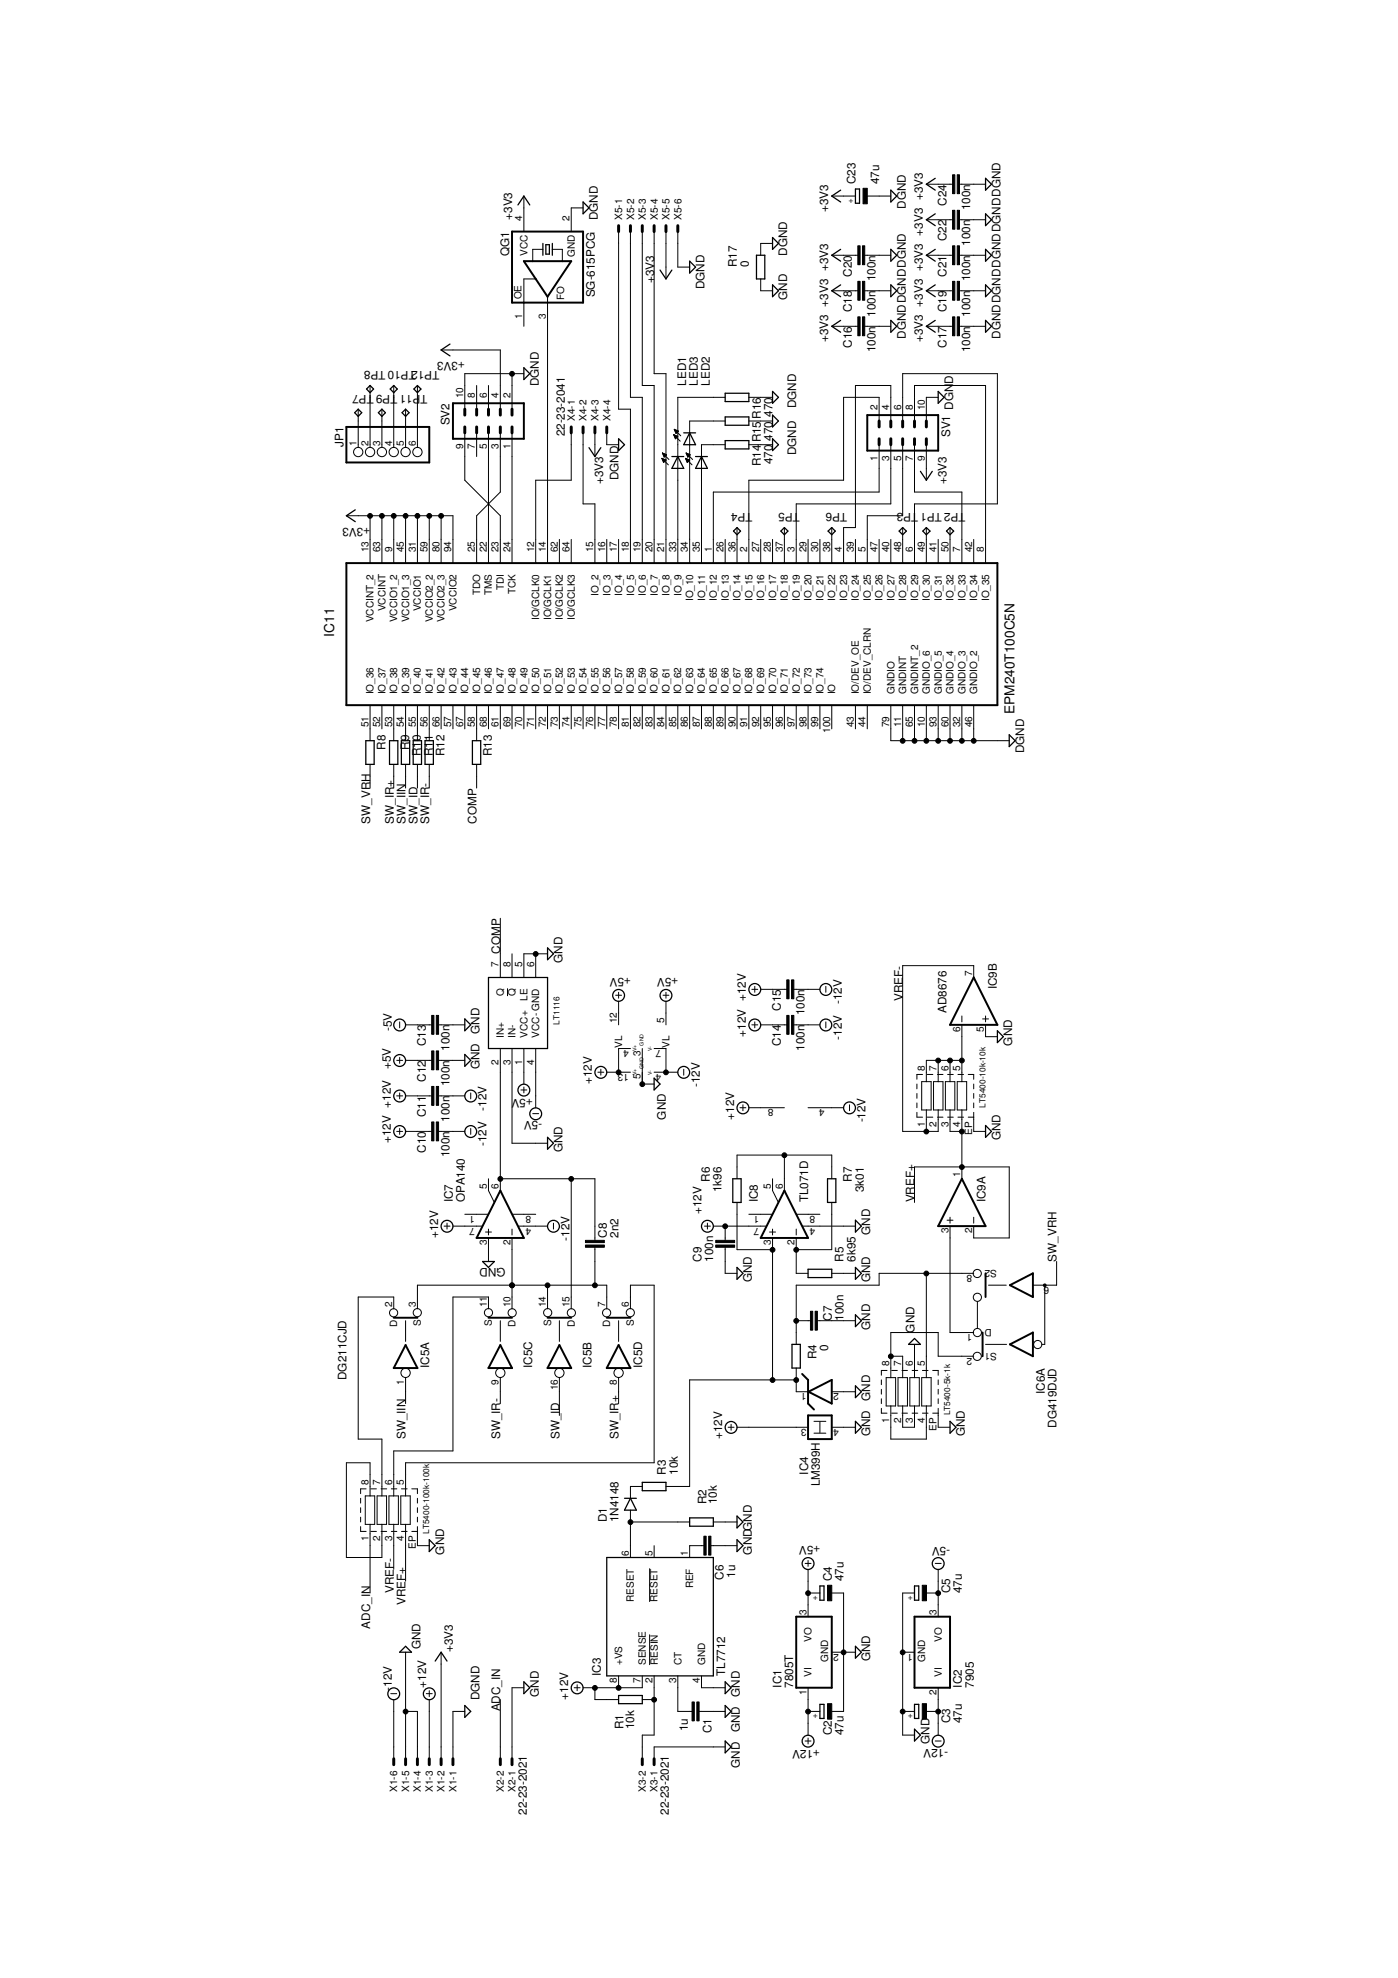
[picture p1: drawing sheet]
<svg xmlns="http://www.w3.org/2000/svg" width="210mm" height="297mm" viewBox="0 0 210 297" stroke-linecap="round" stroke-linejoin="round" font-family="sans-serif">
<defs><g id="words">
<g font-size="2.1">
<text x="50.2" y="95.6" transform="rotate(-90 50.2 95.6)">IC11</text>
<text x="152.3" y="107.2" transform="rotate(-90 152.3 107.2)">EPM240T100C5N</text>
</g>
<g font-size="1.8">
<text x="128.4" y="27.7" transform="rotate(-90 128.4 27.7)">C23</text>
<text x="132" y="27.7" transform="rotate(-90 132 27.7)">47u</text>
<text x="76.9" y="33" transform="rotate(-90 76.9 33)">+3V3</text>
<text x="89.8" y="33.1" transform="rotate(-90 89.8 33.1)">DGND</text>
<text x="124.3" y="31.8" transform="rotate(-90 124.3 31.8)">+3V3</text>
<text x="136" y="31.3" transform="rotate(-90 136 31.3)">DGND</text>
<text x="142.1" y="30.9" transform="rotate(-90 142.1 30.9)">C24</text>
<text x="145.7" y="31.6" transform="rotate(-90 145.7 31.6)">100n</text>
<text x="76.4" y="38.5" transform="rotate(-90 76.4 38.5)">QG1</text>
<text x="110.7" y="40.1" transform="rotate(-90 110.7 40.1)">R17</text>
<text x="112.4" y="40.1" transform="rotate(-90 112.4 40.1)">0</text>
<text x="118.2" y="38.4" transform="rotate(-90 118.2 38.4)">DGND</text>
<text x="127.9" y="41.6" transform="rotate(-90 127.9 41.6)">C20</text>
<text x="142.1" y="41.6" transform="rotate(-90 142.1 41.6)">C21</text>
<text x="142.1" y="36.2" transform="rotate(-90 142.1 36.2)">C22</text>
<text x="145.7" y="36.9" transform="rotate(-90 145.7 36.9)">100n</text>
<text x="89.3" y="44.7" transform="rotate(-90 89.3 44.7)">SG-615PCG</text>
<text x="98.2" y="42.5" transform="rotate(-90 98.2 42.5)">+3V3</text>
<text x="105.8" y="43.4" transform="rotate(-90 105.8 43.4)">DGND</text>
<text x="118.2" y="45" transform="rotate(-90 118.2 45)">GND</text>
<text x="127.9" y="46.9" transform="rotate(-90 127.9 46.9)">C18</text>
<text x="131.5" y="47.6" transform="rotate(-90 131.5 47.6)">100n</text>
<text x="131.5" y="42.3" transform="rotate(-90 131.5 42.3)">100n</text>
<text x="142.1" y="46.9" transform="rotate(-90 142.1 46.9)">C19</text>
<text x="145.7" y="47.6" transform="rotate(-90 145.7 47.6)">100n</text>
<text x="145.7" y="42.3" transform="rotate(-90 145.7 42.3)">100n</text>
<text x="124.3" y="51.4" transform="rotate(-90 124.3 51.4)">+3V3 +3V3 +3V3</text>
<text x="127.9" y="52.2" transform="rotate(-90 127.9 52.2)">C16</text>
<text x="131.5" y="52.9" transform="rotate(-90 131.5 52.9)">100n</text>
<text x="136" y="50.9" transform="rotate(-90 136 50.9)">DGNDDGNDDGND</text>
<text x="138.6" y="51.4" transform="rotate(-90 138.6 51.4)">+3V3 +3V3 +3V3 +3V3 +3V3</text>
<text x="142.1" y="52.2" transform="rotate(-90 142.1 52.2)">C17</text>
<text x="145.7" y="52.9" transform="rotate(-90 145.7 52.9)">100n</text>
<text x="150.2" y="50.9" transform="rotate(-90 150.2 50.9)">DGNDDGNDDGNDDGNDDGND</text>
<text x="64.2" y="59.3" transform="rotate(-180 64.2 59.3)">TP11 TP9 TP7</text>
<text x="66" y="55.8" transform="rotate(-180 66 55.8)">TP12TP10 TP8</text>
<text x="69.8" y="54.3" transform="rotate(-180 69.8 54.3)">+3V3</text>
<text x="80.9" y="58" transform="rotate(-90 80.9 58)">DGND</text>
<text x="103" y="57.9" transform="rotate(-90 103 57.9)">LED1</text>
<text x="104.8" y="57.9" transform="rotate(-90 104.8 57.9)">LED3</text>
<text x="106.6" y="57.9" transform="rotate(-90 106.6 57.9)">LED2</text>
<text x="143.1" y="57.6" transform="rotate(-90 143.1 57.6)">D</text>
<text x="67.5" y="63.9" transform="rotate(-90 67.5 63.9)">SV2</text>
<text x="84.8" y="65.5" transform="rotate(-90 84.8 65.5)">22-23-2041</text>
<text x="116" y="62.6" transform="rotate(-90 116 62.6)">470</text>
<text x="119.5" y="61.3" transform="rotate(-90 119.5 61.3)">DGND</text>
<text x="142.7" y="65.7" transform="rotate(-90 142.7 65.7)">SV1</text>
<text x="143.1" y="61.5" transform="rotate(-90 143.1 61.5)">DGN</text>
<text x="51.6" y="67.1" transform="rotate(-90 51.6 67.1)">JP1</text>
<text x="114.2" y="70" transform="rotate(-90 114.2 70)">R14 R15 R16</text>
<text x="116" y="69.7" transform="rotate(-90 116 69.7)">470</text>
<text x="116" y="66.2" transform="rotate(-90 116 66.2)">470</text>
<text x="119.5" y="68.4" transform="rotate(-90 119.5 68.4)">DGND</text>
<text x="90.6" y="72.7" transform="rotate(-90 90.6 72.7)">+3V3</text>
<text x="92.9" y="72.1" transform="rotate(-90 92.9 72.1)">DGND</text>
<text x="111.9" y="77.1" transform="rotate(-180 111.9 77.1)">P4</text>
<text x="113" y="77.1" transform="rotate(-180 113 77.1)">T</text>
<text x="119" y="77.1" transform="rotate(-180 119 77.1)">P5</text>
<text x="120.1" y="77.1" transform="rotate(-180 120.1 77.1)">T</text>
<text x="127.2" y="77.1" transform="rotate(-180 127.2 77.1)">TP6</text>
<text x="136.8" y="77.1" transform="rotate(-180 136.8 77.1)">P3</text>
<text x="142.1" y="72.7" transform="rotate(-90 142.1 72.7)">+3V3</text>
<text x="143.9" y="77.1" transform="rotate(-180 143.9 77.1)">P2 TP1 T</text>
<text x="145" y="77.1" transform="rotate(-180 145 77.1)">T</text>
<text x="55.6" y="79.2" transform="rotate(-180 55.6 79.2)">+3V3</text>
<text x="57.9" y="112.6" transform="rotate(-90 57.9 112.6)">R8</text>
<text x="61.4" y="112.6" transform="rotate(-90 61.4 112.6)">R9</text>
<text x="63.2" y="113.6" transform="rotate(-90 63.2 113.6)">R10</text>
<text x="65" y="113.6" transform="rotate(-90 65 113.6)">R11</text>
<text x="66.7" y="113.6" transform="rotate(-90 66.7 113.6)">R12</text>
<text x="73.9" y="113.6" transform="rotate(-90 73.9 113.6)">R13</text>
<text x="153.8" y="113.1" transform="rotate(-90 153.8 113.1)">DGND</text>
<text x="55.6" y="123.7" transform="rotate(-90 55.6 123.7)">SW_VRH</text>
<text x="59.1" y="123.7" transform="rotate(-90 59.1 123.7)">SW_IR+</text>
<text x="60.9" y="123.7" transform="rotate(-90 60.9 123.7)">SW_IIN</text>
<text x="62.7" y="123.7" transform="rotate(-90 62.7 123.7)">SW_ID</text>
<text x="64.4" y="123.7" transform="rotate(-90 64.4 123.7)">SW_IR-</text>
<text x="71.6" y="123.7" transform="rotate(-90 71.6 123.7)">COMP</text>
<text x="75.1" y="143.2" transform="rotate(-90 75.1 143.2)">COMP</text>
<text x="84.4" y="144.6" transform="rotate(-90 84.4 144.6)">GND</text>
<text x="94.7" y="146.9" transform="rotate(-180 94.7 146.9)">+5V</text>
<text x="101.8" y="146.9" transform="rotate(-180 101.8 146.9)">+5V</text>
<text x="149.7" y="148.6" transform="rotate(-90 149.7 148.6)">IC9B</text>
<text x="58.9" y="154.9" transform="rotate(-90 58.9 154.9)">-5V</text>
<text x="72" y="155.2" transform="rotate(-90 72 155.2)">GND</text>
<text x="112" y="155.7" transform="rotate(-90 112 155.7)">+12V +12V</text>
<text x="117.2" y="151.8" transform="rotate(-90 117.2 151.8)">C15</text>
<text x="120.8" y="152.5" transform="rotate(-90 120.8 152.5)">100n</text>
<text x="126.4" y="150.8" transform="rotate(-90 126.4 150.8)">-12V</text>
<text x="135.5" y="150.3" transform="rotate(-90 135.5 150.3)">VREF-</text>
<text x="142.1" y="152.1" transform="rotate(-90 142.1 152.1)">AD8676</text>
<text x="58.7" y="160.6" transform="rotate(-90 58.7 160.6)">+5V</text>
<text x="63.9" y="157.1" transform="rotate(-90 63.9 157.1)">C13</text>
<text x="67.5" y="157.8" transform="rotate(-90 67.5 157.8)">100n</text>
<text x="72" y="160.6" transform="rotate(-90 72 160.6)">GND</text>
<text x="117.2" y="157.1" transform="rotate(-90 117.2 157.1)">C14</text>
<text x="120.8" y="157.8" transform="rotate(-90 120.8 157.8)">100n</text>
<text x="126.4" y="156.1" transform="rotate(-90 126.4 156.1)">-12V</text>
<text x="152" y="157" transform="rotate(-90 152 157)">GND</text>
<text x="63.9" y="167.8" transform="rotate(-90 63.9 167.8)">C11</text>
<text x="63.9" y="162.4" transform="rotate(-90 63.9 162.4)">C12</text>
<text x="67.5" y="163.1" transform="rotate(-90 67.5 163.1)">100n</text>
<text x="73.1" y="166.8" transform="rotate(-90 73.1 166.8)">-12V</text>
<text x="80" y="165" transform="rotate(-180 80 165)">+5V</text>
<text x="88.9" y="162.8" transform="rotate(-90 88.9 162.8)">+12V</text>
<text x="105.1" y="163.2" transform="rotate(-90 105.1 163.2)">-12V</text>
<text x="58.7" y="171.7" transform="rotate(-90 58.7 171.7)">+12V +12V</text>
<text x="63.9" y="173.1" transform="rotate(-90 63.9 173.1)">C10</text>
<text x="67.5" y="173.8" transform="rotate(-90 67.5 173.8)">100n</text>
<text x="67.5" y="168.5" transform="rotate(-90 67.5 168.5)">100n</text>
<text x="73.1" y="172.1" transform="rotate(-90 73.1 172.1)">-12V</text>
<text x="81.4" y="168.4" transform="rotate(-180 81.4 168.4)">-5V</text>
<text x="84.4" y="173" transform="rotate(-90 84.4 173)">GND</text>
<text x="100" y="168.1" transform="rotate(-90 100 168.1)">GND</text>
<text x="110.2" y="168.1" transform="rotate(-90 110.2 168.1)">+12V</text>
<text x="129.9" y="168.6" transform="rotate(-90 129.9 168.6)">-12V</text>
<text x="150.2" y="171.2" transform="rotate(-90 150.2 171.2)">GND</text>
<text x="106.6" y="177.5" transform="rotate(-90 106.6 177.5)">R6</text>
<text x="108.4" y="179" transform="rotate(-90 108.4 179)">1k96</text>
<text x="127.9" y="177.5" transform="rotate(-90 127.9 177.5)">R7</text>
<text x="129.7" y="179" transform="rotate(-90 129.7 179)">3k01</text>
<text x="65.8" y="185.9" transform="rotate(-90 65.8 185.9)">+12V</text>
<text x="68" y="180.6" transform="rotate(-90 68 180.6)">IC7</text>
<text x="69.8" y="180.6" transform="rotate(-90 69.8 180.6)">OPA140</text>
<text x="91.1" y="185.9" transform="rotate(-90 91.1 185.9)">C8</text>
<text x="92.9" y="185.9" transform="rotate(-90 92.9 185.9)">2n2</text>
<text x="105.3" y="182.3" transform="rotate(-90 105.3 182.3)">+12V</text>
<text x="113.8" y="180.6" transform="rotate(-90 113.8 180.6)">IC8</text>
<text x="121.3" y="180.6" transform="rotate(-90 121.3 180.6)">TL071D</text>
<text x="130.7" y="185.5" transform="rotate(-90 130.7 185.5)">GND</text>
<text x="137.3" y="180.6" transform="rotate(-90 137.3 180.6)">VREF+</text>
<text x="148" y="180.6" transform="rotate(-90 148 180.6)">IC9A</text>
<text x="75.9" y="190.4" transform="rotate(-180 75.9 190.4)">GND</text>
<text x="85.5" y="186.3" transform="rotate(-90 85.5 186.3)">-12V</text>
<text x="105.3" y="189.5" transform="rotate(-90 105.3 189.5)">C9</text>
<text x="107.1" y="189.5" transform="rotate(-90 107.1 189.5)">100n</text>
<text x="126.7" y="189.5" transform="rotate(-90 126.7 189.5)">R5</text>
<text x="128.4" y="189.5" transform="rotate(-90 128.4 189.5)">6k95</text>
<text x="158.6" y="189.5" transform="rotate(-90 158.6 189.5)">SW_VRH</text>
<text x="112.9" y="192.6" transform="rotate(-90 112.9 192.6)">GND</text>
<text x="130.7" y="192.6" transform="rotate(-90 130.7 192.6)">GND</text>
<text x="124.3" y="202.9" transform="rotate(-90 124.3 202.9)">0</text>
<text x="124.9" y="198.3" transform="rotate(-90 124.9 198.3)">C7</text>
<text x="126.7" y="198.3" transform="rotate(-90 126.7 198.3)">100n</text>
<text x="130.7" y="199.7" transform="rotate(-90 130.7 199.7)">GND</text>
<text x="137.3" y="200.1" transform="rotate(-90 137.3 200.1)">GND</text>
<text x="52" y="207.2" transform="rotate(-90 52 207.2)">DG211CJD</text>
<text x="64.4" y="205.5" transform="rotate(-90 64.4 205.5)">IC5A</text>
<text x="79.9" y="205.5" transform="rotate(-90 79.9 205.5)">IC5C</text>
<text x="88.8" y="205.5" transform="rotate(-90 88.8 205.5)">IC5B</text>
<text x="96.4" y="205.5" transform="rotate(-90 96.4 205.5)">IC5D</text>
<text x="122.6" y="204.1" transform="rotate(-90 122.6 204.1)">R4</text>
<text x="156.9" y="209.3" transform="rotate(-90 156.9 209.3)">IC6A</text>
<text x="130.7" y="215.7" transform="rotate(-90 130.7 215.7)">GND</text>
<text x="130.7" y="210.3" transform="rotate(-90 130.7 210.3)">GND</text>
<text x="144.9" y="215.7" transform="rotate(-90 144.9 215.7)">GND</text>
<text x="158.6" y="214.4" transform="rotate(-90 158.6 214.4)">DG419DJD</text>
<text x="60.9" y="216.1" transform="rotate(-90 60.9 216.1)">SW_IIN</text>
<text x="75.1" y="216.1" transform="rotate(-90 75.1 216.1)">SW_IR-</text>
<text x="84" y="216.1" transform="rotate(-90 84 216.1)">SW_ID</text>
<text x="92.9" y="216.1" transform="rotate(-90 92.9 216.1)">SW_IR+</text>
<text x="100" y="221.5" transform="rotate(-90 100 221.5)">R3</text>
<text x="101.8" y="221.5" transform="rotate(-90 101.8 221.5)">10k</text>
<text x="108.4" y="216.1" transform="rotate(-90 108.4 216.1)">+12V</text>
<text x="121.3" y="221.5" transform="rotate(-90 121.3 221.5)">IC4</text>
<text x="106.1" y="225.9" transform="rotate(-90 106.1 225.9)">R2</text>
<text x="107.6" y="225.9" transform="rotate(-90 107.6 225.9)">10k</text>
<text x="123.1" y="223.2" transform="rotate(-90 123.1 223.2)">LM399H</text>
<text x="66.7" y="233.5" transform="rotate(-90 66.7 233.5)">GND</text>
<text x="91.1" y="228.6" transform="rotate(-90 91.1 228.6)">D1</text>
<text x="92.9" y="228.6" transform="rotate(-90 92.9 228.6)">1N4148</text>
<text x="112.9" y="233.5" transform="rotate(-90 112.9 233.5)">GNDGND</text>
<text x="123.2" y="232.2" transform="rotate(-180 123.2 232.2)">+5V</text>
<text x="142.6" y="232.4" transform="rotate(-180 142.6 232.4)">-5V</text>
<text x="59.1" y="239.2" transform="rotate(-90 59.1 239.2)">VREF-</text>
<text x="108.6" y="237.2" transform="rotate(-90 108.6 237.2)">C6</text>
<text x="110.4" y="236.9" transform="rotate(-90 110.4 236.9)">1u</text>
<text x="124.9" y="237.5" transform="rotate(-90 124.9 237.5)">C4</text>
<text x="126.7" y="237.5" transform="rotate(-90 126.7 237.5)">47u</text>
<text x="142.6" y="239.2" transform="rotate(-90 142.6 239.2)">C5</text>
<text x="144.4" y="239.2" transform="rotate(-90 144.4 239.2)">47u</text>
<text x="55.6" y="244.6" transform="rotate(-90 55.6 244.6)">ADC_IN</text>
<text x="60.9" y="241" transform="rotate(-90 60.9 241)">VREF+</text>
<text x="63.1" y="247.7" transform="rotate(-90 63.1 247.7)">GND</text>
<text x="68" y="248.1" transform="rotate(-90 68 248.1)">+3V3</text>
<text x="90.2" y="251.7" transform="rotate(-90 90.2 251.7)">IC3</text>
<text x="108.9" y="251.7" transform="rotate(-90 108.9 251.7)">TL7712</text>
<text x="130.7" y="249.5" transform="rotate(-90 130.7 249.5)">GND</text>
<text x="58.8" y="253.9" transform="rotate(-90 58.8 253.9)">-12V</text>
<text x="64" y="253.5" transform="rotate(-90 64 253.5)">+12V</text>
<text x="72" y="255.3" transform="rotate(-90 72 255.3)">DGND</text>
<text x="75.1" y="257" transform="rotate(-90 75.1 257)">ADC_IN</text>
<text x="80.9" y="254.8" transform="rotate(-90 80.9 254.8)">GND</text>
<text x="85.3" y="255.2" transform="rotate(-90 85.3 255.2)">+12V</text>
<text x="111.1" y="254.8" transform="rotate(-90 111.1 254.8)">GND</text>
<text x="117.3" y="253.5" transform="rotate(-90 117.3 253.5)">IC1</text>
<text x="119.1" y="253.5" transform="rotate(-90 119.1 253.5)">7805T</text>
<text x="144.4" y="253.5" transform="rotate(-90 144.4 253.5)">IC2</text>
<text x="146.2" y="253.5" transform="rotate(-90 146.2 253.5)">7905</text>
<text x="93.6" y="259.7" transform="rotate(-90 93.6 259.7)">R1</text>
<text x="95.2" y="259.7" transform="rotate(-90 95.2 259.7)">10k</text>
<text x="103.3" y="260" transform="rotate(-90 103.3 260)">1u</text>
<text x="106.8" y="260.3" transform="rotate(-90 106.8 260.3)">C1</text>
<text x="111.1" y="260.1" transform="rotate(-90 111.1 260.1)">GND</text>
<text x="123.1" y="262.8" transform="rotate(-180 123.1 262.8)">+12V</text>
<text x="124.9" y="260.6" transform="rotate(-90 124.9 260.6)">C2</text>
<text x="126.7" y="260.6" transform="rotate(-90 126.7 260.6)">47u</text>
<text x="139.5" y="261.9" transform="rotate(-90 139.5 261.9)">GND</text>
<text x="142.4" y="262.6" transform="rotate(-180 142.4 262.6)">-12V</text>
<text x="142.6" y="258.8" transform="rotate(-90 142.6 258.8)">C3</text>
<text x="144.4" y="258.8" transform="rotate(-90 144.4 258.8)">47u</text>
<text x="111.1" y="265.5" transform="rotate(-90 111.1 265.5)">GND</text>
<text x="79.1" y="272.6" transform="rotate(-90 79.1 272.6)">22-23-2021</text>
<text x="100.4" y="272.6" transform="rotate(-90 100.4 272.6)">22-23-2021</text>
</g>
<g font-size="1.5">
<text x="78.4" y="33.2" transform="rotate(-90 78.4 33.2)">4</text>
<text x="85.5" y="33.2" transform="rotate(-90 85.5 33.2)">2</text>
<text x="93.4" y="33" transform="rotate(-90 93.4 33)">X5-1</text>
<text x="95.2" y="33" transform="rotate(-90 95.2 33)">X5-2</text>
<text x="97" y="33" transform="rotate(-90 97 33)">X5-3</text>
<text x="98.7" y="33" transform="rotate(-90 98.7 33)">X5-4</text>
<text x="100.5" y="33" transform="rotate(-90 100.5 33)">X5-5</text>
<text x="102.3" y="33" transform="rotate(-90 102.3 33)">X5-6</text>
<text x="79.2" y="38.4" transform="rotate(-90 79.2 38.4)">VCC</text>
<text x="86.3" y="38.6" transform="rotate(-90 86.3 38.6)">GND</text>
<text x="78.3" y="45" transform="rotate(-90 78.3 45)">OE</text>
<text x="78.4" y="47.9" transform="rotate(-90 78.4 47.9)">1</text>
<text x="82" y="47.9" transform="rotate(-90 82 47.9)">3</text>
<text x="84.7" y="45.1" transform="rotate(-90 84.7 45.1)">FO</text>
<text x="69.5" y="59.8" transform="rotate(-90 69.5 59.8)">10</text>
<text x="71.3" y="59.8" transform="rotate(-90 71.3 59.8)">8</text>
<text x="73.1" y="59.8" transform="rotate(-90 73.1 59.8)">6</text>
<text x="74.9" y="59.8" transform="rotate(-90 74.9 59.8)">4</text>
<text x="76.6" y="59.8" transform="rotate(-90 76.6 59.8)">2</text>
<text x="86.3" y="63.2" transform="rotate(-90 86.3 63.2)">X4-1</text>
<text x="88.1" y="63.2" transform="rotate(-90 88.1 63.2)">X4-2</text>
<text x="89.9" y="63.2" transform="rotate(-90 89.9 63.2)">X4-3</text>
<text x="91.6" y="63.2" transform="rotate(-90 91.6 63.2)">X4-4</text>
<text x="131.7" y="61.6" transform="rotate(-90 131.7 61.6)">2</text>
<text x="133.5" y="61.6" transform="rotate(-90 133.5 61.6)">4</text>
<text x="135.3" y="61.6" transform="rotate(-90 135.3 61.6)">6</text>
<text x="137.1" y="61.6" transform="rotate(-90 137.1 61.6)">8</text>
<text x="138.8" y="61.6" transform="rotate(-90 138.8 61.6)">10</text>
<text x="53.5" y="66.9" transform="rotate(-90 53.5 66.9)">1</text>
<text x="55.3" y="66.9" transform="rotate(-90 55.3 66.9)">2</text>
<text x="57.1" y="66.9" transform="rotate(-90 57.1 66.9)">3</text>
<text x="58.9" y="66.9" transform="rotate(-90 58.9 66.9)">4</text>
<text x="60.6" y="66.9" transform="rotate(-90 60.6 66.9)">5</text>
<text x="62.4" y="66.9" transform="rotate(-90 62.4 66.9)">6</text>
<text x="69.5" y="67.5" transform="rotate(-90 69.5 67.5)">9</text>
<text x="71.3" y="67.5" transform="rotate(-90 71.3 67.5)">7</text>
<text x="73.1" y="67.5" transform="rotate(-90 73.1 67.5)">5</text>
<text x="74.9" y="67.5" transform="rotate(-90 74.9 67.5)">3</text>
<text x="76.6" y="67.5" transform="rotate(-90 76.6 67.5)">1</text>
<text x="131.7" y="69.2" transform="rotate(-90 131.7 69.2)">1</text>
<text x="133.5" y="69.2" transform="rotate(-90 133.5 69.2)">3</text>
<text x="135.3" y="69.2" transform="rotate(-90 135.3 69.2)">5</text>
<text x="137.1" y="69.2" transform="rotate(-90 137.1 69.2)">7</text>
<text x="138.8" y="69.2" transform="rotate(-90 138.8 69.2)">9</text>
<text x="55.3" y="82.9" transform="rotate(-90 55.3 82.9)">13</text>
<text x="57.1" y="82.9" transform="rotate(-90 57.1 82.9)">63</text>
<text x="58.9" y="82.9" transform="rotate(-90 58.9 82.9)">9</text>
<text x="60.6" y="82.9" transform="rotate(-90 60.6 82.9)">45</text>
<text x="62.4" y="82.9" transform="rotate(-90 62.4 82.9)">31</text>
<text x="64.2" y="82.9" transform="rotate(-90 64.2 82.9)">59</text>
<text x="66" y="82.9" transform="rotate(-90 66 82.9)">80</text>
<text x="67.8" y="82.9" transform="rotate(-90 67.8 82.9)">94</text>
<text x="71.3" y="82.9" transform="rotate(-90 71.3 82.9)">25</text>
<text x="73.1" y="82.9" transform="rotate(-90 73.1 82.9)">22</text>
<text x="74.9" y="82.9" transform="rotate(-90 74.9 82.9)">23</text>
<text x="76.6" y="82.9" transform="rotate(-90 76.6 82.9)">24</text>
<text x="80.2" y="82.9" transform="rotate(-90 80.2 82.9)">12</text>
<text x="82" y="82.9" transform="rotate(-90 82 82.9)">14</text>
<text x="83.7" y="82.9" transform="rotate(-90 83.7 82.9)">62</text>
<text x="85.5" y="82.9" transform="rotate(-90 85.5 82.9)">64</text>
<text x="89.1" y="82.9" transform="rotate(-90 89.1 82.9)">15</text>
<text x="90.9" y="82.9" transform="rotate(-90 90.9 82.9)">16</text>
<text x="92.6" y="82.9" transform="rotate(-90 92.6 82.9)">17</text>
<text x="94.4" y="82.9" transform="rotate(-90 94.4 82.9)">18</text>
<text x="96.2" y="82.9" transform="rotate(-90 96.2 82.9)">19</text>
<text x="98" y="82.9" transform="rotate(-90 98 82.9)">20</text>
<text x="99.7" y="82.9" transform="rotate(-90 99.7 82.9)">21</text>
<text x="101.5" y="82.9" transform="rotate(-90 101.5 82.9)">33</text>
<text x="103.3" y="82.9" transform="rotate(-90 103.3 82.9)">34</text>
<text x="105.1" y="82.9" transform="rotate(-90 105.1 82.9)">35</text>
<text x="106.9" y="82.9" transform="rotate(-90 106.9 82.9)">1</text>
<text x="108.6" y="82.9" transform="rotate(-90 108.6 82.9)">26</text>
<text x="110.4" y="82.9" transform="rotate(-90 110.4 82.9)">36</text>
<text x="112.2" y="82.9" transform="rotate(-90 112.2 82.9)">2</text>
<text x="114" y="82.9" transform="rotate(-90 114 82.9)">27</text>
<text x="115.7" y="82.9" transform="rotate(-90 115.7 82.9)">28</text>
<text x="117.5" y="82.9" transform="rotate(-90 117.5 82.9)">37</text>
<text x="119.3" y="82.9" transform="rotate(-90 119.3 82.9)">3</text>
<text x="121.1" y="82.9" transform="rotate(-90 121.1 82.9)">29</text>
<text x="122.8" y="82.9" transform="rotate(-90 122.8 82.9)">30</text>
<text x="124.6" y="82.9" transform="rotate(-90 124.6 82.9)">38</text>
<text x="126.4" y="82.9" transform="rotate(-90 126.4 82.9)">4</text>
<text x="128.2" y="82.9" transform="rotate(-90 128.2 82.9)">39</text>
<text x="130" y="82.9" transform="rotate(-90 130 82.9)">5</text>
<text x="131.7" y="82.9" transform="rotate(-90 131.7 82.9)">47</text>
<text x="133.5" y="82.9" transform="rotate(-90 133.5 82.9)">40</text>
<text x="135.3" y="82.9" transform="rotate(-90 135.3 82.9)">48</text>
<text x="137.1" y="82.9" transform="rotate(-90 137.1 82.9)">6</text>
<text x="138.8" y="82.9" transform="rotate(-90 138.8 82.9)">49</text>
<text x="140.6" y="82.9" transform="rotate(-90 140.6 82.9)">41</text>
<text x="142.4" y="82.9" transform="rotate(-90 142.4 82.9)">50</text>
<text x="144.2" y="82.9" transform="rotate(-90 144.2 82.9)">7</text>
<text x="146" y="82.9" transform="rotate(-90 146 82.9)">42</text>
<text x="147.7" y="82.9" transform="rotate(-90 147.7 82.9)">8</text>
<text x="72.1" y="89.4" transform="rotate(-90 72.1 89.4)">TDO</text>
<text x="73.9" y="89.4" transform="rotate(-90 73.9 89.4)">TMS</text>
<text x="75.6" y="88.6" transform="rotate(-90 75.6 88.6)">TDI</text>
<text x="77.4" y="89.2" transform="rotate(-90 77.4 89.2)">TCK</text>
<text x="89.9" y="89.5" transform="rotate(-90 89.9 89.5)">IO_2</text>
<text x="91.6" y="89.5" transform="rotate(-90 91.6 89.5)">IO_3</text>
<text x="93.4" y="89.5" transform="rotate(-90 93.4 89.5)">IO_4</text>
<text x="95.2" y="89.5" transform="rotate(-90 95.2 89.5)">IO_5</text>
<text x="97" y="89.5" transform="rotate(-90 97 89.5)">IO_6</text>
<text x="98.7" y="89.5" transform="rotate(-90 98.7 89.5)">IO_7</text>
<text x="100.5" y="89.5" transform="rotate(-90 100.5 89.5)">IO_8</text>
<text x="102.3" y="89.5" transform="rotate(-90 102.3 89.5)">IO_9</text>
<text x="56.1" y="93.5" transform="rotate(-90 56.1 93.5)">VCCINT_2</text>
<text x="57.9" y="91.8" transform="rotate(-90 57.9 91.8)">VCCINT</text>
<text x="59.6" y="93.5" transform="rotate(-90 59.6 93.5)">VCCIO1_2</text>
<text x="61.4" y="93.5" transform="rotate(-90 61.4 93.5)">VCCIO1_3</text>
<text x="63.2" y="91.8" transform="rotate(-90 63.2 91.8)">VCCIO1</text>
<text x="65" y="93.5" transform="rotate(-90 65 93.5)">VCCIO2_2</text>
<text x="66.8" y="93.5" transform="rotate(-90 66.8 93.5)">VCCIO2_3</text>
<text x="68.5" y="91.8" transform="rotate(-90 68.5 91.8)">VCCIO2</text>
<text x="81" y="93.1" transform="rotate(-90 81 93.1)">IO/GCLK0</text>
<text x="82.8" y="93.1" transform="rotate(-90 82.8 93.1)">IO/GCLK1</text>
<text x="84.5" y="93.1" transform="rotate(-90 84.5 93.1)">IO/GCLK2</text>
<text x="86.3" y="93.1" transform="rotate(-90 86.3 93.1)">IO/GCLK3</text>
<text x="104.1" y="90.3" transform="rotate(-90 104.1 90.3)">IO_10</text>
<text x="105.9" y="90.3" transform="rotate(-90 105.9 90.3)">IO_11</text>
<text x="107.6" y="90.3" transform="rotate(-90 107.6 90.3)">IO_12</text>
<text x="109.4" y="90.3" transform="rotate(-90 109.4 90.3)">IO_13</text>
<text x="111.2" y="90.3" transform="rotate(-90 111.2 90.3)">IO_14</text>
<text x="113" y="90.3" transform="rotate(-90 113 90.3)">IO_15</text>
<text x="114.7" y="90.3" transform="rotate(-90 114.7 90.3)">IO_16</text>
<text x="116.5" y="90.3" transform="rotate(-90 116.5 90.3)">IO_17</text>
<text x="118.3" y="90.3" transform="rotate(-90 118.3 90.3)">IO_18</text>
<text x="120.1" y="90.3" transform="rotate(-90 120.1 90.3)">IO_19</text>
<text x="121.9" y="90.3" transform="rotate(-90 121.9 90.3)">IO_20</text>
<text x="123.6" y="90.3" transform="rotate(-90 123.6 90.3)">IO_21</text>
<text x="125.4" y="90.3" transform="rotate(-90 125.4 90.3)">IO_22</text>
<text x="127.2" y="90.3" transform="rotate(-90 127.2 90.3)">IO_23</text>
<text x="129" y="90.3" transform="rotate(-90 129 90.3)">IO_24</text>
<text x="130.7" y="90.3" transform="rotate(-90 130.7 90.3)">IO_25</text>
<text x="132.5" y="90.3" transform="rotate(-90 132.5 90.3)">IO_26</text>
<text x="134.3" y="90.3" transform="rotate(-90 134.3 90.3)">IO_27</text>
<text x="136.1" y="90.3" transform="rotate(-90 136.1 90.3)">IO_28</text>
<text x="137.8" y="90.3" transform="rotate(-90 137.8 90.3)">IO_29</text>
<text x="139.6" y="90.3" transform="rotate(-90 139.6 90.3)">IO_30</text>
<text x="141.4" y="90.3" transform="rotate(-90 141.4 90.3)">IO_31</text>
<text x="143.2" y="90.3" transform="rotate(-90 143.2 90.3)">IO_32</text>
<text x="145" y="90.3" transform="rotate(-90 145 90.3)">IO_33</text>
<text x="146.7" y="90.3" transform="rotate(-90 146.7 90.3)">IO_34</text>
<text x="148.5" y="90.3" transform="rotate(-90 148.5 90.3)">IO_35</text>
<text x="56.1" y="104.3" transform="rotate(-90 56.1 104.3)">IO_36</text>
<text x="57.9" y="104.3" transform="rotate(-90 57.9 104.3)">IO_37</text>
<text x="59.6" y="104.3" transform="rotate(-90 59.6 104.3)">IO_38</text>
<text x="61.4" y="104.3" transform="rotate(-90 61.4 104.3)">IO_39</text>
<text x="63.2" y="104.3" transform="rotate(-90 63.2 104.3)">IO_40</text>
<text x="65" y="104.3" transform="rotate(-90 65 104.3)">IO_41</text>
<text x="66.7" y="104.3" transform="rotate(-90 66.7 104.3)">IO_42</text>
<text x="68.5" y="104.3" transform="rotate(-90 68.5 104.3)">IO_43</text>
<text x="70.3" y="104.3" transform="rotate(-90 70.3 104.3)">IO_44</text>
<text x="72.1" y="104.3" transform="rotate(-90 72.1 104.3)">IO_45</text>
<text x="73.9" y="104.3" transform="rotate(-90 73.9 104.3)">IO_46</text>
<text x="75.6" y="104.3" transform="rotate(-90 75.6 104.3)">IO_47</text>
<text x="77.4" y="104.3" transform="rotate(-90 77.4 104.3)">IO_48</text>
<text x="79.2" y="104.3" transform="rotate(-90 79.2 104.3)">IO_49</text>
<text x="81" y="104.3" transform="rotate(-90 81 104.3)">IO_50</text>
<text x="82.7" y="104.3" transform="rotate(-90 82.7 104.3)">IO_51</text>
<text x="84.5" y="104.3" transform="rotate(-90 84.5 104.3)">IO_52</text>
<text x="86.3" y="104.3" transform="rotate(-90 86.3 104.3)">IO_53</text>
<text x="88.1" y="104.3" transform="rotate(-90 88.1 104.3)">IO_54</text>
<text x="89.9" y="104.3" transform="rotate(-90 89.9 104.3)">IO_55</text>
<text x="91.6" y="104.3" transform="rotate(-90 91.6 104.3)">IO_56</text>
<text x="93.4" y="104.3" transform="rotate(-90 93.4 104.3)">IO_57</text>
<text x="95.2" y="104.3" transform="rotate(-90 95.2 104.3)">IO_58</text>
<text x="97" y="104.3" transform="rotate(-90 97 104.3)">IO_59</text>
<text x="98.7" y="104.3" transform="rotate(-90 98.7 104.3)">IO_60</text>
<text x="100.5" y="104.3" transform="rotate(-90 100.5 104.3)">IO_61</text>
<text x="102.3" y="104.3" transform="rotate(-90 102.3 104.3)">IO_62</text>
<text x="104.1" y="104.3" transform="rotate(-90 104.1 104.3)">IO_63</text>
<text x="105.8" y="104.3" transform="rotate(-90 105.8 104.3)">IO_64</text>
<text x="107.6" y="104.3" transform="rotate(-90 107.6 104.3)">IO_65</text>
<text x="109.4" y="104.3" transform="rotate(-90 109.4 104.3)">IO_66</text>
<text x="111.2" y="104.3" transform="rotate(-90 111.2 104.3)">IO_67</text>
<text x="113" y="104.3" transform="rotate(-90 113 104.3)">IO_68</text>
<text x="114.7" y="104.3" transform="rotate(-90 114.7 104.3)">IO_69</text>
<text x="116.5" y="104.3" transform="rotate(-90 116.5 104.3)">IO_70</text>
<text x="118.3" y="104.3" transform="rotate(-90 118.3 104.3)">IO_71</text>
<text x="120.1" y="104.3" transform="rotate(-90 120.1 104.3)">IO_72</text>
<text x="121.8" y="104.3" transform="rotate(-90 121.8 104.3)">IO_73</text>
<text x="123.6" y="104.3" transform="rotate(-90 123.6 104.3)">IO_74</text>
<text x="125.4" y="104.3" transform="rotate(-90 125.4 104.3)">IO</text>
<text x="129" y="104.3" transform="rotate(-90 129 104.3)">IO/DEV_OE</text>
<text x="130.7" y="104.3" transform="rotate(-90 130.7 104.3)">IO/DEV_CLRN</text>
<text x="134.3" y="104.3" transform="rotate(-90 134.3 104.3)">GNDIO</text>
<text x="136.1" y="104.3" transform="rotate(-90 136.1 104.3)">GNDINT</text>
<text x="137.8" y="104.3" transform="rotate(-90 137.8 104.3)">GNDINT_2</text>
<text x="139.6" y="104.3" transform="rotate(-90 139.6 104.3)">GNDIO_6</text>
<text x="141.4" y="104.3" transform="rotate(-90 141.4 104.3)">GNDIO_5</text>
<text x="143.2" y="104.3" transform="rotate(-90 143.2 104.3)">GNDIO_4</text>
<text x="145" y="104.3" transform="rotate(-90 145 104.3)">GNDIO_3</text>
<text x="146.7" y="104.3" transform="rotate(-90 146.7 104.3)">GNDIO_2</text>
<text x="55.3" y="109.2" transform="rotate(-90 55.3 109.2)">51</text>
<text x="57.1" y="109.2" transform="rotate(-90 57.1 109.2)">52</text>
<text x="58.9" y="109.2" transform="rotate(-90 58.9 109.2)">53</text>
<text x="60.6" y="109.2" transform="rotate(-90 60.6 109.2)">54</text>
<text x="62.4" y="109.2" transform="rotate(-90 62.4 109.2)">55</text>
<text x="64.2" y="109.2" transform="rotate(-90 64.2 109.2)">56</text>
<text x="66" y="109.2" transform="rotate(-90 66 109.2)">66</text>
<text x="67.8" y="109.2" transform="rotate(-90 67.8 109.2)">57</text>
<text x="69.5" y="109.2" transform="rotate(-90 69.5 109.2)">67</text>
<text x="71.3" y="109.2" transform="rotate(-90 71.3 109.2)">58</text>
<text x="73.1" y="109.2" transform="rotate(-90 73.1 109.2)">68</text>
<text x="74.9" y="109.2" transform="rotate(-90 74.9 109.2)">61</text>
<text x="76.6" y="109.2" transform="rotate(-90 76.6 109.2)">69</text>
<text x="78.4" y="109.2" transform="rotate(-90 78.4 109.2)">70</text>
<text x="80.2" y="109.2" transform="rotate(-90 80.2 109.2)">71</text>
<text x="82" y="109.2" transform="rotate(-90 82 109.2)">72</text>
<text x="83.7" y="109.2" transform="rotate(-90 83.7 109.2)">73</text>
<text x="85.5" y="109.2" transform="rotate(-90 85.5 109.2)">74</text>
<text x="87.3" y="109.2" transform="rotate(-90 87.3 109.2)">75</text>
<text x="89.1" y="109.2" transform="rotate(-90 89.1 109.2)">76</text>
<text x="90.9" y="109.2" transform="rotate(-90 90.9 109.2)">77</text>
<text x="92.6" y="109.2" transform="rotate(-90 92.6 109.2)">78</text>
<text x="94.4" y="109.2" transform="rotate(-90 94.4 109.2)">81</text>
<text x="96.2" y="109.2" transform="rotate(-90 96.2 109.2)">82</text>
<text x="98" y="109.2" transform="rotate(-90 98 109.2)">83</text>
<text x="99.7" y="109.2" transform="rotate(-90 99.7 109.2)">84</text>
<text x="101.5" y="109.2" transform="rotate(-90 101.5 109.2)">85</text>
<text x="103.3" y="109.2" transform="rotate(-90 103.3 109.2)">86</text>
<text x="105.1" y="109.2" transform="rotate(-90 105.1 109.2)">87</text>
<text x="106.9" y="109.2" transform="rotate(-90 106.9 109.2)">88</text>
<text x="108.6" y="109.2" transform="rotate(-90 108.6 109.2)">89</text>
<text x="110.4" y="109.2" transform="rotate(-90 110.4 109.2)">90</text>
<text x="112.2" y="109.2" transform="rotate(-90 112.2 109.2)">91</text>
<text x="114" y="109.2" transform="rotate(-90 114 109.2)">92</text>
<text x="115.7" y="109.2" transform="rotate(-90 115.7 109.2)">95</text>
<text x="117.5" y="109.2" transform="rotate(-90 117.5 109.2)">96</text>
<text x="119.3" y="109.2" transform="rotate(-90 119.3 109.2)">97</text>
<text x="121.1" y="109.2" transform="rotate(-90 121.1 109.2)">98</text>
<text x="122.8" y="109.2" transform="rotate(-90 122.8 109.2)">99</text>
<text x="124.6" y="110" transform="rotate(-90 124.6 110)">100</text>
<text x="128.2" y="109.2" transform="rotate(-90 128.2 109.2)">43</text>
<text x="130" y="109.2" transform="rotate(-90 130 109.2)">44</text>
<text x="133.5" y="109.2" transform="rotate(-90 133.5 109.2)">79</text>
<text x="135.3" y="109.2" transform="rotate(-90 135.3 109.2)">11</text>
<text x="137.1" y="109.2" transform="rotate(-90 137.1 109.2)">65</text>
<text x="138.8" y="109.2" transform="rotate(-90 138.8 109.2)">10</text>
<text x="140.6" y="109.2" transform="rotate(-90 140.6 109.2)">93</text>
<text x="142.4" y="109.2" transform="rotate(-90 142.4 109.2)">60</text>
<text x="144.2" y="109.2" transform="rotate(-90 144.2 109.2)">32</text>
<text x="146" y="109.2" transform="rotate(-90 146 109.2)">46</text>
<text x="74.9" y="145.2" transform="rotate(-90 74.9 145.2)">7</text>
<text x="75.6" y="149.6" transform="rotate(-90 75.6 149.6)">Q</text>
<text x="76.6" y="145.2" transform="rotate(-90 76.6 145.2)">8</text>
<text x="77.4" y="149.6" transform="rotate(-90 77.4 149.6)">Q</text>
<text x="78.4" y="145.2" transform="rotate(-90 78.4 145.2)">5</text>
<text x="80.2" y="145.2" transform="rotate(-90 80.2 145.2)">6</text>
<text x="146" y="146.5" transform="rotate(-90 146 146.5)">7</text>
<text x="75.6" y="155.8" transform="rotate(-90 75.6 155.8)">IN+</text>
<text x="77.4" y="155.8" transform="rotate(-90 77.4 155.8)">IN-</text>
<text x="79.2" y="150.3" transform="rotate(-90 79.2 150.3)">LE</text>
<text x="79.2" y="155.8" transform="rotate(-90 79.2 155.8)">VCC+</text>
<text x="81" y="155.8" transform="rotate(-90 81 155.8)">VCC- GND</text>
<text x="92.6" y="153.6" transform="rotate(-90 92.6 153.6)">12</text>
<text x="99.7" y="153.6" transform="rotate(-90 99.7 153.6)">5</text>
<text x="144.2" y="155" transform="rotate(-90 144.2 155)">6</text>
<text x="147.7" y="155" transform="rotate(-90 147.7 155)">5</text>
<text x="74.9" y="159.9" transform="rotate(-90 74.9 159.9)">2</text>
<text x="76.6" y="159.9" transform="rotate(-90 76.6 159.9)">3</text>
<text x="78.4" y="159.9" transform="rotate(-90 78.4 159.9)">1</text>
<text x="80.2" y="159.9" transform="rotate(-90 80.2 159.9)">4</text>
<text x="93.4" y="157.4" transform="rotate(-90 93.4 157.4)">VL</text>
<text x="94.4" y="161.3" transform="rotate(-180 94.4 161.3)">13</text>
<text x="94.4" y="157.7" transform="rotate(-180 94.4 157.7)">4</text>
<text x="96.2" y="158.5" transform="rotate(-90 96.2 158.5)">3</text>
<text x="99.3" y="161.3" transform="rotate(-180 99.3 161.3)">4</text>
<text x="99.3" y="157.7" transform="rotate(-180 99.3 157.7)">7</text>
<text x="100.5" y="157.4" transform="rotate(-90 100.5 157.4)">VL</text>
<text x="138.8" y="160.8" transform="rotate(-90 138.8 160.8)">8</text>
<text x="140.6" y="160.8" transform="rotate(-90 140.6 160.8)">7</text>
<text x="142.4" y="160.8" transform="rotate(-90 142.4 160.8)">6</text>
<text x="144.2" y="160.8" transform="rotate(-90 144.2 160.8)">5</text>
<text x="96.2" y="162.1" transform="rotate(-90 96.2 162.1)">5</text>
<text x="116.1" y="166.6" transform="rotate(-180 116.1 166.6)">8</text>
<text x="123.8" y="166.6" transform="rotate(-180 123.8 166.6)">4</text>
<text x="138.8" y="169.2" transform="rotate(-90 138.8 169.2)">1</text>
<text x="140.6" y="169.2" transform="rotate(-90 140.6 169.2)">2</text>
<text x="142.4" y="169.2" transform="rotate(-90 142.4 169.2)">3</text>
<text x="144.2" y="169.2" transform="rotate(-90 144.2 169.2)">4</text>
<text x="146" y="170.4" transform="rotate(-90 146 170.4)">EP</text>
<text x="73.1" y="178.5" transform="rotate(-90 73.1 178.5)">5</text>
<text x="74.9" y="178.5" transform="rotate(-90 74.9 178.5)">6</text>
<text x="115.7" y="178.5" transform="rotate(-90 115.7 178.5)">5</text>
<text x="117.5" y="178.5" transform="rotate(-90 117.5 178.5)">6</text>
<text x="144.2" y="176.8" transform="rotate(-90 144.2 176.8)">1</text>
<text x="71.3" y="182.6" transform="rotate(-180 71.3 182.6)">1</text>
<text x="71.3" y="184.4" transform="rotate(-180 71.3 184.4)">7</text>
<text x="79.7" y="182.6" transform="rotate(-180 79.7 182.6)">8</text>
<text x="79.7" y="184.4" transform="rotate(-180 79.7 184.4)">4</text>
<text x="114" y="182.6" transform="rotate(-180 114 182.6)">1</text>
<text x="114" y="184.4" transform="rotate(-180 114 184.4)">7</text>
<text x="122.4" y="182.6" transform="rotate(-180 122.4 182.6)">8</text>
<text x="122.4" y="184.4" transform="rotate(-180 122.4 184.4)">4</text>
<text x="142.4" y="185.2" transform="rotate(-90 142.4 185.2)">3</text>
<text x="146" y="185.2" transform="rotate(-90 146 185.2)">2</text>
<text x="73.1" y="187" transform="rotate(-90 73.1 187)">3</text>
<text x="76.6" y="187" transform="rotate(-90 76.6 187)">2</text>
<text x="115.7" y="187" transform="rotate(-90 115.7 187)">3</text>
<text x="119.3" y="187" transform="rotate(-90 119.3 187)">2</text>
<text x="146" y="191.5" transform="rotate(-180 146 191.5)">8</text>
<text x="149.7" y="190.7" transform="rotate(-180 149.7 190.7)">S2</text>
<text x="58.9" y="196.3" transform="rotate(-90 58.9 196.3)">2</text>
<text x="62.4" y="196.3" transform="rotate(-90 62.4 196.3)">3</text>
<text x="73.1" y="196.3" transform="rotate(-90 73.1 196.3)">11</text>
<text x="76.6" y="196.3" transform="rotate(-90 76.6 196.3)">10</text>
<text x="82" y="196.3" transform="rotate(-90 82 196.3)">14</text>
<text x="85.5" y="196.3" transform="rotate(-90 85.5 196.3)">15</text>
<text x="90.9" y="196.3" transform="rotate(-90 90.9 196.3)">7</text>
<text x="94.4" y="196.3" transform="rotate(-90 94.4 196.3)">6</text>
<text x="157.6" y="193.3" transform="rotate(-180 157.6 193.3)">6</text>
<text x="59.6" y="199.3" transform="rotate(-90 59.6 199.3)">D</text>
<text x="63.2" y="199.2" transform="rotate(-90 63.2 199.2)">S</text>
<text x="73.9" y="199.2" transform="rotate(-90 73.9 199.2)">S</text>
<text x="77.4" y="199.3" transform="rotate(-90 77.4 199.3)">D</text>
<text x="82.8" y="199.2" transform="rotate(-90 82.8 199.2)">S</text>
<text x="86.3" y="199.3" transform="rotate(-90 86.3 199.3)">D</text>
<text x="91.6" y="199.3" transform="rotate(-90 91.6 199.3)">D</text>
<text x="95.2" y="199.2" transform="rotate(-90 95.2 199.2)">S</text>
<text x="146" y="200.4" transform="rotate(-180 146 200.4)">1</text>
<text x="146" y="203.9" transform="rotate(-180 146 203.9)">2</text>
<text x="148.9" y="199.6" transform="rotate(-180 148.9 199.6)">D</text>
<text x="149.7" y="203.1" transform="rotate(-180 149.7 203.1)">S1</text>
<text x="60.6" y="207.9" transform="rotate(-90 60.6 207.9)">1</text>
<text x="74.9" y="207.9" transform="rotate(-90 74.9 207.9)">9</text>
<text x="83.7" y="208.8" transform="rotate(-90 83.7 208.8)">16</text>
<text x="92.6" y="207.9" transform="rotate(-90 92.6 207.9)">8</text>
<text x="121.1" y="209.3" transform="rotate(-180 121.1 209.3)">1</text>
<text x="125.9" y="209.3" transform="rotate(-180 125.9 209.3)">2</text>
<text x="133.5" y="205.2" transform="rotate(-90 133.5 205.2)">8</text>
<text x="135.3" y="205.2" transform="rotate(-90 135.3 205.2)">7</text>
<text x="137.1" y="205.2" transform="rotate(-90 137.1 205.2)">6</text>
<text x="138.8" y="205.2" transform="rotate(-90 138.8 205.2)">5</text>
<text x="121.1" y="214.6" transform="rotate(-180 121.1 214.6)">3</text>
<text x="125.9" y="214.6" transform="rotate(-180 125.9 214.6)">4</text>
<text x="133.5" y="213.6" transform="rotate(-90 133.5 213.6)">1</text>
<text x="135.3" y="213.6" transform="rotate(-90 135.3 213.6)">2</text>
<text x="137.1" y="213.6" transform="rotate(-90 137.1 213.6)">3</text>
<text x="138.8" y="213.6" transform="rotate(-90 138.8 213.6)">4</text>
<text x="140.6" y="214.8" transform="rotate(-90 140.6 214.8)">EP</text>
<text x="55.3" y="223" transform="rotate(-90 55.3 223)">8</text>
<text x="57.1" y="223" transform="rotate(-90 57.1 223)">7</text>
<text x="58.9" y="223" transform="rotate(-90 58.9 223)">6</text>
<text x="60.6" y="223" transform="rotate(-90 60.6 223)">5</text>
<text x="55.3" y="231.4" transform="rotate(-90 55.3 231.4)">1</text>
<text x="57.1" y="231.4" transform="rotate(-90 57.1 231.4)">2</text>
<text x="58.9" y="231.4" transform="rotate(-90 58.9 231.4)">3</text>
<text x="60.6" y="231.4" transform="rotate(-90 60.6 231.4)">4</text>
<text x="62.4" y="232.6" transform="rotate(-90 62.4 232.6)">EP</text>
<text x="94.4" y="233.6" transform="rotate(-90 94.4 233.6)">6</text>
<text x="98" y="233.6" transform="rotate(-90 98 233.6)">5</text>
<text x="103.3" y="233.6" transform="rotate(-90 103.3 233.6)">1</text>
<text x="104.1" y="238.5" transform="rotate(-90 104.1 238.5)">REF</text>
<text x="95.2" y="240.5" transform="rotate(-90 95.2 240.5)">RESET</text>
<text x="98.7" y="240.5" transform="rotate(-90 98.7 240.5)">RESET</text>
<text x="121.1" y="242.5" transform="rotate(-90 121.1 242.5)">3</text>
<text x="140.6" y="242.5" transform="rotate(-90 140.6 242.5)">3</text>
<text x="93.4" y="250" transform="rotate(-90 93.4 250)">+VS</text>
<text x="97" y="250" transform="rotate(-90 97 250)">SENSE</text>
<text x="98.7" y="250" transform="rotate(-90 98.7 250)">RESIN</text>
<text x="102.3" y="250" transform="rotate(-90 102.3 250)">CT</text>
<text x="105.9" y="250" transform="rotate(-90 105.9 250)">GND</text>
<text x="121.8" y="246.6" transform="rotate(-90 121.8 246.6)">VO</text>
<text x="121.9" y="251.8" transform="rotate(-90 121.9 251.8)">VI</text>
<text x="124.3" y="249.5" transform="rotate(-90 124.3 249.5)">GND</text>
<text x="125.9" y="248.4" transform="rotate(-180 125.9 248.4)">2</text>
<text x="137.1" y="248.4" transform="rotate(-180 137.1 248.4)">1</text>
<text x="138.9" y="249.5" transform="rotate(-90 138.9 249.5)">GND</text>
<text x="141.4" y="246.6" transform="rotate(-90 141.4 246.6)">VO</text>
<text x="141.4" y="251.8" transform="rotate(-90 141.4 251.8)">VI</text>
<text x="92.6" y="252.7" transform="rotate(-90 92.6 252.7)">8</text>
<text x="96.2" y="252.7" transform="rotate(-90 96.2 252.7)">7</text>
<text x="98" y="252.7" transform="rotate(-90 98 252.7)">2</text>
<text x="101.5" y="252.7" transform="rotate(-90 101.5 252.7)">3</text>
<text x="105.1" y="252.7" transform="rotate(-90 105.1 252.7)">4</text>
<text x="121.1" y="254.5" transform="rotate(-90 121.1 254.5)">1</text>
<text x="140.6" y="254.5" transform="rotate(-90 140.6 254.5)">2</text>
<text x="59.6" y="269.1" transform="rotate(-90 59.6 269.1)">X1-6</text>
<text x="61.4" y="269.1" transform="rotate(-90 61.4 269.1)">X1-5</text>
<text x="63.2" y="269.1" transform="rotate(-90 63.2 269.1)">X1-4</text>
<text x="65" y="269.1" transform="rotate(-90 65 269.1)">X1-3</text>
<text x="66.7" y="269.1" transform="rotate(-90 66.7 269.1)">X1-2</text>
<text x="68.5" y="269.1" transform="rotate(-90 68.5 269.1)">X1-1</text>
<text x="75.6" y="269.1" transform="rotate(-90 75.6 269.1)">X2-2</text>
<text x="77.4" y="269.1" transform="rotate(-90 77.4 269.1)">X2-1</text>
<text x="97" y="269.1" transform="rotate(-90 97 269.1)">X3-2</text>
<text x="98.7" y="269.1" transform="rotate(-90 98.7 269.1)">X3-1</text>
</g>
<g font-size="1.2">
<text x="128.1" y="29.9" transform="rotate(-180 128.1 29.9)">+</text>
<text x="84" y="153.9" transform="rotate(-90 84 153.9)">LT1116</text>
<text x="148" y="166.3" transform="rotate(-90 148 166.3)">LT5400-10k-10k</text>
<text x="142.6" y="212.6" transform="rotate(-90 142.6 212.6)">LT5400-5k-1k</text>
<text x="64.4" y="230.3" transform="rotate(-90 64.4 230.3)">LT5400-100k-100k</text>
<text x="122.8" y="239.6" transform="rotate(-180 122.8 239.6)">+</text>
<text x="137" y="239.6" transform="rotate(-180 137 239.6)">+</text>
<text x="122.8" y="257.4" transform="rotate(-180 122.8 257.4)">+</text>
<text x="137" y="257.4" transform="rotate(-180 137 257.4)">+</text>
</g>
<g font-size=".8">
<text x="95.5" y="161.5" transform="rotate(-90 95.5 161.5)">V+</text>
<text x="95.5" y="157.9" transform="rotate(-90 95.5 157.9)">V+</text>
<text x="96.6" y="160.6" transform="rotate(-90 96.6 160.6)">GND</text>
<text x="96.6" y="157" transform="rotate(-90 96.6 157)">GND</text>
<text x="97.9" y="161.5" transform="rotate(-90 97.9 161.5)">V-</text>
<text x="97.9" y="157.9" transform="rotate(-90 97.9 157.9)">V-</text>
</g>
</g></defs>
<g fill="none" stroke="#000" stroke-width=".15">
<path d="M78.7 29.4v5.4M81.5 37.4h-1.5v1.8M82.9 37.4h1.5v1.8M87.5 31.2h-1.7v3.6M92.9 34.8v26.6h1.8v23.2M94.7 34.8v24.9h1.7v24.9M96.4 34.8v23.1h1.8v26.7M98.2 34.8v21.3h1.8v28.5M100 34.8v7.1M101.8 34.8v5.3h1.7M116 36.6h-1.8v1.7M124.9 29.4h3.5"/>
<path d="M124.9 38.3h3.9M129.9 38.3h3.9M130.2 29.4h3.6M139.1 38.3h3.9M139.1 33h3.9M139.1 27.7h3.9M144.1 38.3h3.9M144.1 33h3.9M144.1 27.7h3.9M55.6 57.9v9.3M59.1 57.9v9.3M62.7 57.9v9.3"/>
<path d="M66.2 52.6h8.9v8.8M71.6 57.9v3.5M73.3 57.9v3.5M76.9 56.1v5.3M78.7 56.1h-8.9v5.3M80.4 41.9h-1.7v7.1M82.2 44.6v40M108.9 59.7h-7.1v24.9M112.4 59.7h3.6M114.2 41.9v1.8h1.8M124.9 49h3.9M124.9 43.7h3.9"/>
<path d="M129.9 49h3.9M129.9 43.7h3.9M139.1 49h3.9M139.1 43.7h3.9M140.9 59.7h-1.8v3.5M144.1 49h3.9M144.1 43.7h3.9M52 77.4h16v7.2M53.8 61.4v5.8M55.6 77.4v7.2M57.3 61.4v5.8M57.3 77.4v7.2"/>
<path d="M59.1 77.4v7.2M60.9 61.4v5.8M60.9 77.4v7.2M62.7 77.4v7.2M64.5 77.4v7.2M66.2 77.4v7.2M69.8 65v7.1l5.3 5.3v7.2M71.6 65v3.6M73.3 65v19.6M75.1 65v8.9l-3.5 3.5v7.2M76.9 65v19.6M85.8 65v7.1h-5.4v12.5"/>
<path d="M87.5 65v10.7h1.8v8.9M89.3 65v3.6M91.1 65v1.8h1.8M99.4 68.8l1 1M99.4 68.8l.6 .3-.4 .3zM99.4 68.8v.1M99.5 68l.9 1M99.5 68.9v.1M99.5 68l.2 .6 .4-.3M99.5 68l.6 .3M99.5 68h.1M99.5 68.1v.1"/>
<path d="M99.5 68.9v.3M99.6 68.1v.3M99.6 68.9v.5M99.7 68.1v.5M99.7 69v.4M99.8 68.2v.4M99.8 69v.3M99.8 68.2v.3M99.9 68.2v.3M99.9 69.1v.1M100.1 68.3h.1M101.2 65.3l.9 1"/>
<path d="M101.2 65.3l.2 .6M101.2 65.3l.6 .2-.4 .4M101.2 65.3v.1M101.2 64.5l1 .9M101.2 64.5l.3 .6 .4-.4M101.2 64.5l.7 .2M101.3 64.5h.1M101.3 65.3v.2M101.3 64.5v.2M101.3 65.4v.3M101.4 64.6v.3M101.4 65.4v.5"/>
<path d="M101.5 64.6v.4M101.5 65.4v.4M101.6 64.6v.4M101.6 65.4v.3M101.6 65.5v.2M101.7 64.7v.2M101.7 65.5v.1M101.8 64.7v.1M101.9 64.7h.1M102.9 68.8l1 1M102.9 68.8l.6 .3-.3 .3zM103 68.9v.1"/>
<path d="M103 68l1 1M103 68l.3 .6M103 68l.6 .3-.3 .3M103.1 68.1h.1M103.1 68.9v.2M103.1 68.1v.2M103.1 68.9v.4M103.2 68.1v.4M103.2 69v.4M103.3 68.1v.5M103.3 69v.4M103.4 68.2v.4"/>
<path d="M103.4 69v.3M103.4 68.2v.3M103.4 69v.2M103.5 68.2v.2M103.5 69.1h.1M103.6 68.3h.1M108.9 63.2h-5.4v21.4M108.9 66.8h-3.6v17.8M110.7 79.2v5.4M112.4 63.2h3.6M112.4 66.8h3.6M117.8 79.2v5.4"/>
<path d="M124.9 79.2v5.4M132 66.8v7.1h-24.9v10.7M132 63.2v-3.5h-5.3v12.4h-14.3v12.5M133.8 66.8v8.9h-14.3v8.9M133.8 63.2v-5.3h-5.4v21.3h-1.7v5.4M135.5 66.8v10.6h-5.3v7.2M135.5 63.2v-7.1h14.3v19.6h-12.5v8.9M135.5 79.2v5.4M137.3 66.8v7.1h7.1v10.7M137.3 63.2v-5.3h10.7v26.7M139.1 66.8v5.3M139.1 79.2v5.4"/>
<path d="M142.6 79.2v5.4M84 81v3.6M85.8 81v3.6M91.1 81v3.6M92.9 81v3.6M108.9 81v3.6M114.2 81v3.6M116 81v3.6M121.3 81v3.6M123.1 81v3.6M128.4 81v3.6M132 81v3.6"/>
<path d="M133.8 81v3.6M140.9 81v3.6M146.2 81v3.6M55.6 105.9v5.3M55.6 114.8v3.5M57.3 105.9v3.6M59.1 105.9v5.3M59.1 114.8v3.5M60.9 105.9v5.3M60.9 114.8v3.5M62.7 105.9v5.3M62.7 114.8v3.5"/>
<path d="M64.5 105.9v5.3M64.5 114.8v3.5M66.2 105.9v3.6M68 105.9v3.6M69.8 105.9v3.6M71.6 105.9v5.3M71.6 114.8v3.5M73.3 105.9v3.6M75.1 105.9v3.6M76.9 105.9v3.6M78.7 105.9v3.6M80.4 105.9v3.6"/>
<path d="M82.2 105.9v3.6M84 105.9v3.6M85.8 105.9v3.6M87.5 105.9v3.6M89.3 105.9v3.6M91.1 105.9v3.6M92.9 105.9v3.6M94.7 105.9v3.6M96.4 105.9v3.6M98.2 105.9v3.6M100 105.9v3.6M101.8 105.9v3.6"/>
<path d="M103.5 105.9v3.6M105.3 105.9v3.6M107.1 105.9v3.6M108.9 105.9v3.6M110.7 105.9v3.6M112.4 105.9v3.6M114.2 105.9v3.6M116 105.9v3.6M117.8 105.9v3.6M119.5 105.9v3.6M121.3 105.9v3.6M123.1 105.9v3.6"/>
<path d="M124.9 105.9v3.6M128.4 105.9v3.6M130.2 105.9v3.6M133.8 105.9v5.3h17.7M135.5 105.9v5.3M137.3 105.9v5.3M139.1 105.9v5.3M140.9 105.9v5.3M142.6 105.9v5.3M144.4 105.9v5.3M146.2 105.9v5.3M75.1 137.9v8.9"/>
<path d="M59.6 159.2h.9M60 153.5v.8M60 158.8v.9M60.9 153.9h3.9M60.9 159.2h3.9M65.9 153.9h3.9M65.9 159.2h3.9M75.1 157.5v21.3M76.2 148.4v1.2M76.9 143.2v3.6M76.9 157.5v14.2h5.3M78.7 157.5v5.3"/>
<path d="M80.4 143.2v3.6M80.4 157.5v8.8M82.2 143.2h-3.5v3.6M92.4 149.5h.9M92.9 149v.9M92.9 150.3v3.6M94.7 157.5h-1.8v3.5M96.4 157.5v5.3h1.8M98.2 157.5h1.8v3.5M99.5 149.5h.9M100 149v.9M100 150.3v3.6"/>
<path d="M112.9 153.9h.9M112.9 148.6h.9M113.3 148.1v.9M113.3 153.5v.8M114.2 153.9h3.9M114.2 148.6h3.9M119.2 153.9h3.9M119.2 148.6h3.9M124 148.1v.9M124 153.5v.8M140.9 159.2v3.2M142.6 159.2v3.2"/>
<path d="M144.4 152.6v.9M144.4 153.9v8.5M144.4 159.2h-5.3v3.2M146.2 146.8v-1.8h-10.7v24.9h5.4v-3.2M147.5 153h.9M148 152.6v.9M148 153.9v1.8h1.8M59.6 169.9h.9M59.6 164.6h.9M60 164.1v.9M60 169.5v.8M60.9 169.9h3.9"/>
<path d="M60.9 164.6h3.9M65.9 169.9h3.9M65.9 164.6h3.9M70.7 164.1v.9M70.7 169.5v.8M73.3 177v1.8l.9 1.7M75.1 177h14.2v9.2M78.2 163.7h.9M78.7 163.2v.9M80 167.2h.9M85.8 177v19.6M89.8 161h.9"/>
<path d="M90.2 160.6v.9M91.1 161h3.6M98.2 161h3.6M102.7 160.6v.9M110.7 177v-3.5h14.2v3.5M111.1 166.3h.9M111.5 165.9v.9M112.4 166.3h5.4M116 177v1.8l.8 1.7M117.8 173.5v5.3M121.3 166.3h5.4M127.6 165.9v.9"/>
<path d="M137.7 167v.8h.8M137.7 162.8v.7M137.7 164.2v.7M137.7 165.6v.7M138.4 162.4h1.4v4.3h-1.4zM138.5 161.4h-.8v.7M139.1 166.7v3.2M139.2 167.8h.9M139.2 161.4h.9M140.2 162.4h1.4v4.3h-1.4zM140.8 167.8h.8M140.8 161.4h.8"/>
<path d="M141.9 162.4h1.5v4.3h-1.5zM142.3 167.8h.8M142.3 161.4h.8M142.6 166.7v3.2h1.8M143.7 162.4h1.4v4.3h-1.4zM143.8 167.8h.9M143.8 161.4h.9M144.4 166.7v10.3M145.4 161.4h.8v.7M145.4 167.8h.8M146.2 162.8v.7M146.2 164.2v.7"/>
<path d="M146.2 165.6v.7M146.2 167v2.9h1.8M59.1 196.6v-1.8h-5.3v21.3h3.5v8.5M60.9 198.3v3.1M62.7 196.6v-3.6h28.4v3.6M66.7 184.1h.9M67.1 183.7v.9M68 184.1h4.4M69.8 182.4h3.5M72.9 185h.9M73.3 196.6v-1.8h-5.3v23.1h-8.9v6.7M73.3 184.6v.9"/>
<path d="M73.3 185.9v3.5M75.1 198.3v3.1M76.9 184.6v.9M76.9 185.9v10.7M76.9 182.4h3.5M77.9 184.1h4.3M82.2 193v3.6M83.1 183.7v.9M84 198.3v3.1M89.3 187.3v5.7M92.9 198.3v3.1M94.7 196.6v-3.6h3.5v26.7h-37.3v4.9"/>
<path d="M105.8 184.1h.9M106.2 183.7v.9M107.1 184.1h7.9M108.9 187.3v3.9h1.8M108.9 184.1v2.1M110.7 180.6v7.1h5.3M112.4 182.4h3.5M115.5 185h.9M116 184.6v.9M116 185.9v21.3M119.5 185.9v5.3h1.8M119.5 184.6v.9"/>
<path d="M119.5 198.3h2.2M119.6 182.4h3.5M120.5 184.1h7.9M122.7 198.3h5.7M124.9 191.2h3.5M124.9 180.6v7.1h-5.4M137.3 180.6v-5.4h14.2v10.7h-5.3v-1.8M139.1 191.2v15.7M142.2 183.2h.9M142.6 182.8v.9M142.6 184.1v16h3.6M146.2 191.2h-14.2v1.8h-12.5v8.9"/>
<path d="M146.2 182.8v.9M146.7 195.5v3.9M148.4 193h2.7M156.9 193.1v8.8h-.5M158.6 189.4v3.6h-3.5M60.9 206.8v4M75.1 206.8v4M84 206.8v5.8M92.9 206.8v4M109.3 214.3h.9M109.8 213.9v.9M110.7 214.3h10.6"/>
<path d="M119.5 205.4v3.6h1.8M119.5 207.2h-16v16h-3.5M122.2 215.2h1.8M122.2 213.4h1.8M123.1 213.5v1.7M124.9 209h3.5M124.9 214.3h3.5M132.3 211.5v.7h.9M132.3 207.2v.7M132.3 208.6v.8M132.3 210.1v.7M133.1 206.9h1.4v4.2h-1.4z"/>
<path d="M133.2 205.8h-.9v.7M133.8 211.1v5h5.3v-5M133.8 203.7h1.7v3.2M133.9 212.2h.8M133.9 205.8h.8M134.8 206.9h1.4v4.2h-1.4zM135.4 212.2h.8M135.4 205.8h.8M135.5 211.1v3.2h1.8v-3.2M136.6 206.9h1.4v4.2h-1.4zM136.9 212.2h.9M136.9 205.8h.9"/>
<path d="M137.3 201.9v5M138.4 206.9h1.4v4.2h-1.4zM138.5 212.2h.8M138.5 205.8h.8M140 205.8h.9v.7M140 212.2h.9M140.9 211.5v2.8h1.7M140.9 207.2v.7M140.9 208.6v.8M140.9 210.1v.7M146.2 203.7h-5.3v-3.6h-7.1v6.8M148 201.9h3.1"/>
<path d="M54.1 229.3v.7h.9M54.1 225v.7M54.1 226.4v.7M54.1 227.8v.8M54.8 224.6h1.5v4.3h-1.5zM55 223.6h-.9v.7M55.6 224.6v-4.9h-3.6v14.2h5.3v-5M55.6 228.9v10.3M55.7 230h.8M55.7 223.6h.8M56.6 224.6h1.4v4.3h-1.4zM57.2 230h.9"/>
<path d="M57.2 223.6h.9M58.4 224.6h1.4v4.3h-1.4zM58.8 230h.8M58.8 223.6h.8M59.1 228.9v6.8M60.2 224.6h1.4v4.3h-1.4zM60.3 230h.8M60.3 223.6h.8M60.9 228.9v8.5M61.8 223.6h.9v.7M61.8 230h.9M62.7 225v.7"/>
<path d="M62.7 226.4v.7M62.7 227.8v.8M62.7 229.3v2.8h1.8M94.7 226.8v7.1M94.7 228.6h8.8M96.4 223.2h-1.7v1.8M97.5 235.5v5.1M98.2 232.1v1.8M105.7 232.1h-2.2v1.8M106.7 232.1h4M107.1 228.6h3.6M120.9 234.8h.9"/>
<path d="M121.3 239.2h1.8M121.3 234.3v.9M121.3 235.7v7.1M124.9 239.2h1.8v17.8h-1.8M137.3 239.2h-1.8v21.4h1.8M139.1 239.2h1.8M140.4 234.8h.9M140.9 235.7v7.1M58.7 254.3h.9M59.1 255.2v8.9M60.9 248.1v16M60.9 257h1.8v7.1"/>
<path d="M64 254.3h.9M64.5 253.9v.9M64.5 255.2v8.9M66.2 248.1v16M69.8 257h-1.8v7.1M75.1 255.2v8.9M78.7 253.4h-1.8v10.7M86.2 253.4h.9M86.7 253v.9M89.3 253.4v1.8h3.6M92.9 251.7v1.7M96.4 251.7v1.7h-8.9"/>
<path d="M96.4 255.2h1.8M97.5 245.4v4.6M98.2 251.7v8.9h-1.8v3.5M101.8 251.7v5.3h2.1M105 257h3.9M105.3 251.7v1.7h3.6M121.3 257h1.8M121.3 253.4v7.2M124.9 248.1h3.5M135.5 248.1h1.8M135.5 257h1.8M139.1 257h1.8"/>
<path d="M140.9 253.4v7.2M108.9 262.3h-10.7v1.8M120.9 261.5h.9M121.3 261v.9M140.4 261.5h.9"/>
<circle cx="53.8" cy="67.9" r=".7"/>
<circle cx="55.6" cy="67.9" r=".7"/>
<circle cx="57.3" cy="67.9" r=".7"/>
<circle cx="59.1" cy="67.9" r=".7"/>
<circle cx="60.9" cy="67.9" r=".7"/>
<circle cx="62.7" cy="67.9" r=".7"/>
<circle cx="59.1" cy="197.1" r=".61"/>
<circle cx="62.7" cy="197.1" r=".61"/>
<circle cx="73.3" cy="197.1" r=".61"/>
<circle cx="76.9" cy="197.1" r=".61"/>
<circle cx="82.2" cy="197.1" r=".61"/>
<circle cx="85.8" cy="197.1" r=".61"/>
<circle cx="91.1" cy="197.1" r=".61"/>
<circle cx="94.6" cy="197.1" r=".61"/>
<circle cx="146.7" cy="191.2" r=".61"/>
<circle cx="146.7" cy="194.8" r=".61"/>
<circle cx="60.9" cy="206.2" r=".7"/>
<circle cx="75.1" cy="206.2" r=".7"/>
<circle cx="84" cy="206.2" r=".7"/>
<circle cx="92.9" cy="206.2" r=".7"/>
<circle cx="146.7" cy="203.7" r=".61"/>
<circle cx="146.7" cy="200.1" r=".61"/>
<circle cx="155.8" cy="201.9" r=".61"/>
</g>
<g fill="none" stroke="#000" stroke-width=".3">
<path d="M76.9 34.8h10.6v10.6h-10.6zM78.7 39.2h7.1l-3.6 5.4zM52 64.1h12.5v5.3h-12.5zM68 60.6h10.7v5.3h-10.7zM130.2 62.3h10.7v5.4h-10.7zM52 84.6h97.8v21.3h-97.8zM146.2 146.8l3.6 7.1h-7.2zM75.1 178.8l3.6 7.1h-7.1zM117.8 178.8l3.5 7.1h-7.1zM144.4 177l3.6 7.1h-7.1zM59.1 197.9h3.6M73.3 197.9h3.6"/>
<path d="M82.2 197.9h3.6M91.1 197.9h3.6M148 191.2v3.6M151.6 193l3.5-1.8v3.6zM60.9 202l1.8 3.4h-3.6zM75.1 202l1.8 3.4h-3.6zM84 202l1.8 3.4h-3.6zM92.9 202l1.8 3.4h-3.6zM120.4 206.3l.9 .9v3.6l.9 .9M121.3 212.6h3.6v3.5h-3.6zM121.4 209l3.5-1.8v3.6zM147.5 200.1v3.6"/>
<path d="M151.6 201.9l3.5-1.8v3.6zM119.5 242.8h5.4v10.6h-5.4zM137.3 242.8h5.3v10.6h-5.3z"/>
</g>
<g fill="none" stroke="#000" stroke-width=".19">
<path d="M77.8 30.8l.9-1.4 .8 1.4M81.5 36.6v1.7M82 36.7h.5v1.5h-.5zM82.9 36.6v1.7M87.5 30.3l.9 .9-.9 .9zM103.5 39.2l.9 .9-.9 .9zM113.6 38.3h1.2v3.6h-1.2zM116 35.7l.9 .9-.9 .8zM126.2 37.4l-1.3 .9 1.3 .9M126.2 28.6l-1.3 .8 1.3 .9M128.4 28.4h.7v2.1h-.7zM133.8 28.6l.8 .8-.8 .9z"/>
<path d="M133.8 37.4l.8 .9-.8 .9zM140.4 37.4l-1.3 .9 1.3 .9M140.4 32.1l-1.3 .9 1.3 .9M140.4 26.8l-1.3 .9 1.3 .9M148 26.8l.9 .9-.9 .9zM148 32.1l.9 .9-.9 .9zM148 37.4l.9 .9-.9 .9zM55 58.4l.6-.5 .5 .5-.5 .6zM58.6 58.4l.5-.5 .5 .5-.5 .6zM62.1 58.4l.6-.5 .5 .5-.5 .6zM67.6 51.7l-1.4 .9 1.4 .8M78.7 55.2l.8 .9-.8 .9z"/>
<path d="M99.1 40.6l.9 1.3 .9-1.3M108.9 59.1h3.5v1.2h-3.5zM116 42.8l.9 .9-.9 .9zM116 58.8l.9 .9-.9 .9zM126.2 48.1l-1.3 .9 1.3 .9M126.2 42.8l-1.3 .9 1.3 .9M133.8 42.8l.8 .9-.8 .9zM133.8 48.1l.8 .9-.8 .9zM140.4 48.1l-1.3 .9 1.3 .9M140.4 42.8l-1.3 .9 1.3 .9M140.9 58.8l.9 .9-.9 .9zM148 42.8l.9 .9-.9 .9z"/>
<path d="M148 48.1l.9 .9-.9 .9zM53.3 62l.5-.6 .5 .6-.5 .5zM53.3 76.6l-1.3 .8 1.3 .9M56.8 62l.5-.6 .6 .6-.6 .5zM60.4 62l.5-.6 .5 .6-.5 .5zM88.4 67.2l.9 1.4 .9-1.4M92.9 65.9l.9 .9-.9 .9zM100.9 68.6h1.8M101.8 68.6l.9 1.7h-1.8zM102.7 65h1.7M103.5 65l.9 1.8h-1.7zM104.4 68.6h1.8"/>
<path d="M105.3 68.6l.9 1.7h-1.8zM108.9 62.6h3.5v1.3h-3.5zM108.9 66.2h3.5v1.2h-3.5zM110.1 79.8l.6-.6 .5 .6-.5 .5zM116 62.3l.9 .9-.9 .9zM116 65.9l.9 .9-.9 .9zM117.8 79.2l.5 .6-.5 .5-.6-.5zM124.3 79.8l.6-.6 .5 .6-.5 .5zM135 79.8l.5-.6 .6 .6-.6 .5zM138.2 70.8l.9 1.3 .9-1.3M139.1 79.2l.5 .6-.5 .5-.5-.5zM142.6 79.2l.6 .6-.6 .5-.5-.5z"/>
<path d="M54.9 111.2h1.3v3.6h-1.3zM58.5 111.2h1.2v3.6h-1.2zM60.3 111.2h1.2v3.6h-1.2zM62 111.2h1.3v3.6h-1.3zM63.8 111.2h1.3v3.6h-1.3zM70.9 111.2h1.3v3.6h-1.3zM151.5 110.3l.9 .9-.9 .9zM69.8 153l.9 .9-.9 .9zM69.8 158.3l.9 .9-.9 .9zM73.3 146.8h8.9v10.7h-8.9zM82.2 142.3l.9 .9-.9 .9zM149.8 154.8l.8 .9-.8 .9z"/>
<path d="M82.2 170.8l.9 .9-.9 .9zM98.2 161.9l.9 .9-.9 .9zM110 177h1.3v3.6h-1.3zM124.2 177h1.3v3.6h-1.3zM148 169l.9 .9-.9 .9zM72.5 189.4h1.7l-.9 .9zM110.7 190.3l.8 .9-.8 .9zM121.3 190.6h3.6v1.3h-3.6zM128.4 183.2l.9 .9-.9 .9zM128.4 190.3l.9 .9-.9 .9zM128.4 197.4l.9 .9-.9 .9zM118.9 201.9h1.3v3.5h-1.3z"/>
<path d="M128.4 208.1l.9 .9-.9 .9zM128.4 213.4l.9 .9-.9 .9zM136.4 201.9l.9-.9 .9 .9zM142.6 213.4l.9 .9-.9 .9zM64.5 231.2l.8 .9-.8 .9zM91.1 233.9h16v17.8h-16zM93.8 225h1.7M94.7 225l.8 1.8h-1.7zM96.4 222.6h3.6v1.3h-3.6zM103.5 227.9h3.6v1.3h-3.6zM110.7 227.7l.8 .9-.8 .8zM110.7 231.2l.8 .9-.8 .9z"/>
<path d="M123.1 238.2h.6v2.1h-.6zM137.3 238.2h.6v2.1h-.6zM60.9 247.2l.9 .9h-1.8zM65.3 249.4l.9-1.3 .9 1.3M69.8 256.1l.9 .9-.9 .9zM78.7 252.6l.8 .8-.8 .9zM92.9 254.6h3.5v1.2h-3.5zM108.9 252.6l.9 .8-.9 .9zM108.9 256.1l.9 .9-.9 .9zM123.1 255.9h.6v2.2h-.6zM128.4 247.2l.9 .9-.9 .9zM137.3 255.9h.6v2.2h-.6z"/>
<path d="M137.3 259.7l.9 .9-.9 .9zM108.9 261.5l.9 .8-.9 .9z"/>
<circle cx="60" cy="159.3" r=".89"/>
<circle cx="60" cy="153.9" r=".89"/>
<circle cx="92.9" cy="149.5" r=".89"/>
<circle cx="100" cy="149.5" r=".89"/>
<circle cx="113.3" cy="148.6" r=".89"/>
<circle cx="113.3" cy="153.9" r=".89"/>
<circle cx="124" cy="148.6" r=".89"/>
<circle cx="124" cy="153.9" r=".89"/>
<circle cx="60" cy="164.6" r=".89"/>
<circle cx="60" cy="169.9" r=".89"/>
<circle cx="70.7" cy="164.6" r=".89"/>
<circle cx="70.7" cy="169.9" r=".89"/>
<circle cx="78.7" cy="163.7" r=".89"/>
<circle cx="80.4" cy="167.3" r=".89"/>
<circle cx="90.2" cy="161" r=".89"/>
<circle cx="102.7" cy="161" r=".89"/>
<circle cx="111.5" cy="166.4" r=".89"/>
<circle cx="127.6" cy="166.4" r=".89"/>
<circle cx="67.1" cy="184.2" r=".89"/>
<circle cx="83.1" cy="184.2" r=".89"/>
<circle cx="106.2" cy="184.2" r=".89"/>
<circle cx="109.8" cy="214.4" r=".89"/>
<circle cx="121.3" cy="234.8" r=".89"/>
<circle cx="140.9" cy="234.8" r=".89"/>
<circle cx="59.1" cy="254.4" r=".89"/>
<circle cx="64.5" cy="254.4" r=".89"/>
<circle cx="86.7" cy="253.5" r=".89"/>
<circle cx="121.3" cy="261.5" r=".89"/>
<circle cx="140.9" cy="261.5" r=".89"/>
</g>
<g fill="#000" stroke="#000" stroke-width=".15">
<path d="M128.8 36.9h.3v2.9h-.3zM129.5 36.9h.3v2.9h-.3zM129.6 28.3h.6v2.3h-.6zM143 36.9h.4v2.9h-.4zM143 31.6h.4v2.8h-.4zM143 26.2h.4v2.9h-.4zM143.7 36.9h.4v2.9h-.4zM143.7 31.6h.4v2.8h-.4zM143.7 26.2h.4v2.9h-.4zM128.8 47.6h.3v2.8h-.3zM128.8 42.2h.3v2.9h-.3zM129.5 47.6h.3v2.8h-.3z"/>
<path d="M129.5 42.2h.3v2.9h-.3zM143 47.6h.4v2.8h-.4zM143 42.2h.4v2.9h-.4zM143.7 47.6h.4v2.8h-.4zM143.7 42.2h.4v2.9h-.4zM64.8 152.5h.4v2.8h-.4zM65.5 152.5h.3v2.8h-.3zM118.1 152.5h.4v2.8h-.4zM118.1 147.2h.4v2.8h-.4zM118.9 152.5h.3v2.8h-.3zM118.9 147.2h.3v2.8h-.3zM64.8 157.8h.4v2.9h-.4z"/>
<path d="M64.8 168.5h.4v2.8h-.4zM64.8 163.2h.4v2.8h-.4zM65.5 157.8h.3v2.9h-.3zM65.5 168.5h.3v2.8h-.3zM65.5 163.2h.3v2.8h-.3zM87.9 186.3h2.8v.3h-2.8zM87.9 187h2.8v.3h-2.8zM107.5 186.3h2.8v.3h-2.8zM107.5 187h2.8v.3h-2.8zM121.7 196.9h.3v2.8h-.3zM122.4 196.9h.3v2.8h-.3zM105.7 230.7h.3v2.8h-.3z"/>
<path d="M106.4 230.7h.3v2.8h-.3zM103.9 255.6h.3v2.8h-.3zM104.6 255.6h.4v2.8h-.4zM124.2 255.8h.7v2.4h-.7zM124.2 238.1h.7v2.3h-.7zM138.5 255.8h.6v2.4h-.6zM138.5 238.1h.6v2.3h-.6z"/>
</g>
<g fill="none" stroke="#000" stroke-width=".44">
<path d="M92.9 33.9v.9M94.7 33.9v.9M96.4 33.9v.9M98.2 33.9v.9M100 33.9v.9M101.8 33.9v.9M69.8 61.4v.9M69.8 64.1v.9M71.6 61.4v.9M71.6 64.1v.9M73.3 61.4v.9M73.3 64.1v.9"/>
<path d="M75.1 61.4v.9M75.1 64.1v.9M76.9 61.4v.9M76.9 64.1v.9M85.8 64.1v.9M87.5 64.1v.9M89.3 64.1v.9M91.1 64.1v.9M132 63.2v.9M132 65.9v.9M133.8 63.2v.9M133.8 65.9v.9"/>
<path d="M135.5 63.2v.9M135.5 65.9v.9M137.3 63.2v.9M137.3 65.9v.9M139.1 63.2v.9M139.1 65.9v.9M59.1 264.1v.9M60.9 264.1v.9M62.7 264.1v.9M64.5 264.1v.9M66.2 264.1v.9M68 264.1v.9"/>
<path d="M75.1 264.1v.9M76.9 264.1v.9M96.4 264.1v.9M98.2 264.1v.9"/>
</g>
<circle cx="156.9" cy="193" r=".17" fill="none" stroke="#000" stroke-width=".23"/>
<g fill="#000" stroke="#000" stroke-width=".15">
<circle cx="76.9" cy="56.1" r=".36"/>
<circle cx="55.6" cy="77.5" r=".36"/>
<circle cx="57.3" cy="77.5" r=".36"/>
<circle cx="59.1" cy="77.5" r=".36"/>
<circle cx="60.9" cy="77.5" r=".36"/>
<circle cx="62.7" cy="77.5" r=".36"/>
<circle cx="64.5" cy="77.5" r=".36"/>
<circle cx="66.2" cy="77.5" r=".36"/>
<circle cx="135.5" cy="111.3" r=".36"/>
<circle cx="137.3" cy="111.3" r=".36"/>
<circle cx="139.1" cy="111.3" r=".36"/>
<circle cx="140.9" cy="111.3" r=".36"/>
<circle cx="142.6" cy="111.3" r=".36"/>
<circle cx="144.4" cy="111.3" r=".36"/>
<circle cx="146.2" cy="111.3" r=".36"/>
<circle cx="80.4" cy="143.3" r=".36"/>
<circle cx="140.9" cy="159.3" r=".36"/>
<circle cx="142.6" cy="159.3" r=".36"/>
<circle cx="144.4" cy="159.3" r=".36"/>
<circle cx="75.1" cy="177" r=".36"/>
<circle cx="85.8" cy="177" r=".36"/>
<circle cx="92.9" cy="161" r=".36"/>
<circle cx="96.4" cy="162.8" r=".36"/>
<circle cx="100" cy="161" r=".36"/>
<circle cx="117.8" cy="173.5" r=".36"/>
<circle cx="139.1" cy="169.9" r=".36"/>
<circle cx="144.4" cy="169.9" r=".36"/>
<circle cx="144.4" cy="175.3" r=".36"/>
<circle cx="76.9" cy="193" r=".36"/>
<circle cx="82.2" cy="193" r=".36"/>
<circle cx="89.3" cy="193" r=".36"/>
<circle cx="108.9" cy="184.1" r=".36"/>
<circle cx="116" cy="187.7" r=".36"/>
<circle cx="119.5" cy="187.7" r=".36"/>
<circle cx="119.5" cy="198.4" r=".36"/>
<circle cx="139.1" cy="191.2" r=".36"/>
<circle cx="116" cy="207.2" r=".36"/>
<circle cx="119.5" cy="207.2" r=".36"/>
<circle cx="133.8" cy="203.7" r=".36"/>
<circle cx="94.7" cy="228.6" r=".36"/>
<circle cx="121.3" cy="239.2" r=".36"/>
<circle cx="140.9" cy="239.2" r=".36"/>
<circle cx="60.9" cy="257" r=".36"/>
<circle cx="89.3" cy="253.5" r=".36"/>
<circle cx="92.9" cy="253.5" r=".36"/>
<circle cx="98.2" cy="255.2" r=".36"/>
<circle cx="121.3" cy="257" r=".36"/>
<circle cx="126.7" cy="248.1" r=".36"/>
<circle cx="135.5" cy="248.1" r=".36"/>
<circle cx="135.5" cy="257" r=".36"/>
<circle cx="140.9" cy="257" r=".36"/>
</g>
<use href="#words"/>
</svg>
